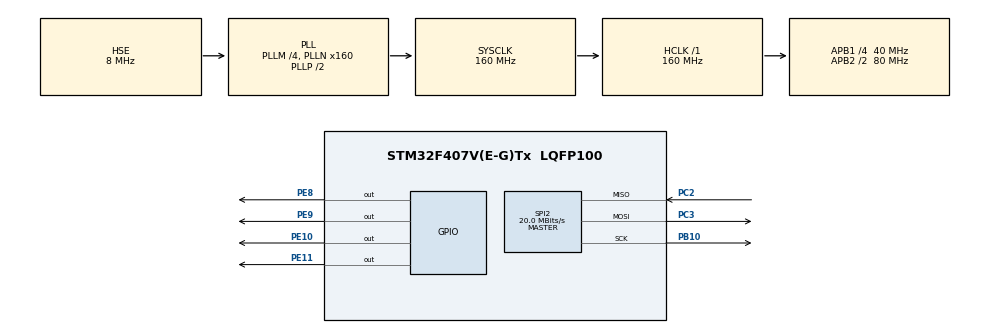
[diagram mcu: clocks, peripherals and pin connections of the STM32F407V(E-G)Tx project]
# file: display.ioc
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ADC1.Channel-0\#ChannelRegularConversion=ADC_CHANNEL_TEMPSENSOR
ADC1.ClockPrescaler=ADC_CLOCK_SYNC_PCLK_DIV8
ADC1.NbrOfConversionFlag=1
ADC1.Rank-0\#ChannelRegularConversion=1
ADC1.SamplingTime-0\#ChannelRegularConversion=ADC_SAMPLETIME_3CYCLES
ADC1.master=1
Mcu.Family=STM32F4
Mcu.Name=STM32F407V(E-G)Tx
Mcu.Package=LQFP100
NVIC.PriorityGroup=NVIC_PRIORITYGROUP_4
PA13.Mode=Trace_Asynchronous_SW
PA13.Signal=SYS_JTMS-SWDIO
PA14.Mode=Trace_Asynchronous_SW
PA14.Signal=SYS_JTCK-SWCLK
PB10.Mode=Full_Duplex_Master
PB10.Signal=SPI2_SCK
PB3.Mode=Trace_Asynchronous_SW
PB3.Signal=SYS_JTDO-SWO
PC14-OSC32_IN.Mode=LSE-External-Oscillator
PC14-OSC32_IN.Signal=RCC_OSC32_IN
PC15-OSC32_OUT.Mode=LSE-External-Oscillator
PC15-OSC32_OUT.Signal=RCC_OSC32_OUT
PC2.Mode=Full_Duplex_Master
PC2.Signal=SPI2_MISO
PC3.Mode=Full_Duplex_Master
PC3.Signal=SPI2_MOSI
PE10.GPIO_ModeDefaultOutputPP=GPIO_MODE_OUTPUT_PP
PE10.GPIO_PuPd=GPIO_NOPULL
PE10.GPIO_Speed=GPIO_SPEED_FREQ_HIGH
PE10.Signal=GPIO_Output
PE11.GPIO_ModeDefaultOutputPP=GPIO_MODE_OUTPUT_PP
PE11.GPIO_PuPd=GPIO_NOPULL
PE11.GPIO_Speed=GPIO_SPEED_FREQ_HIGH
PE11.Signal=GPIO_Output
PE8.GPIO_ModeDefaultOutputPP=GPIO_MODE_OUTPUT_PP
PE8.GPIO_PuPd=GPIO_NOPULL
PE8.GPIO_Speed=GPIO_SPEED_FREQ_HIGH
PE8.Signal=GPIO_Output
PE9.GPIO_ModeDefaultOutputPP=GPIO_MODE_OUTPUT_PP
PE9.GPIO_PuPd=GPIO_NOPULL
PE9.GPIO_Speed=GPIO_SPEED_FREQ_HIGH
PE9.Signal=GPIO_Output
PH0-OSC_IN.Mode=HSE-External-Oscillator
PH0-OSC_IN.Signal=RCC_OSC_IN
PH1-OSC_OUT.Mode=HSE-External-Oscillator
PH1-OSC_OUT.Signal=RCC_OSC_OUT
ProjectManager.HeapSize=0x200
ProjectManager.StackSize=0x400
ProjectManager.TargetToolchain=MDK-ARM V5.32
RCC.48MHZClocksFreq_Value=80000000
RCC.AHBFreq_Value=160000000
RCC.APB1CLKDivider=RCC_HCLK_DIV4
RCC.APB1Freq_Value=40000000
RCC.APB1TimFreq_Value=80000000
RCC.APB2CLKDivider=RCC_HCLK_DIV2
RCC.APB2Freq_Value=80000000
RCC.APB2TimFreq_Value=160000000
RCC.CortexFreq_Value=160000000
RCC.HCLKFreq_Value=160000000
RCC.HSE_VALUE=8000000
RCC.HSI_VALUE=16000000
RCC.PLLM=4
RCC.PLLN=160
RCC.PLLSourceVirtual=RCC_PLLSOURCE_HSE
RCC.RCC_RTC_Clock_Source=RCC_RTCCLKSOURCE_LSE
RCC.SYSCLKFreq_VALUE=160000000
RCC.SYSCLKSource=RCC_SYSCLKSOURCE_PLLCLK
RCC.VCOOutputFreq_Value=320000000
SPI2.BaudRatePrescaler=SPI_BAUDRATEPRESCALER_2
SPI2.CalculateBaudRate=20.0 MBits/s
SPI2.Direction=SPI_DIRECTION_2LINES
SPI2.Mode=SPI_MODE_MASTER
SPI2.VirtualType=VM_MASTER
VP_ADC1_TempSens_Input.Mode=IN-TempSens
VP_RTC_VS_RTC_Activate.Mode=RTC_Enabled
board=custom

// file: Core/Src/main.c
/* USER CODE BEGIN Header */
/**
  ******************************************************************************
  * @file           : main.c
  * @brief          : Main program body
  ******************************************************************************
  * @attention
  *
  * <h2><center>&copy; Copyright (c) 2022 STMicroelectronics.
  * All rights reserved.</center></h2>
  *
  * This software component is licensed by ST under BSD 3-Clause license,
  * the "License"; You may not use this file except in compliance with the
  * License. You may obtain a copy of the License at:
  *                        opensource.org/licenses/BSD-3-Clause
  *
  ******************************************************************************
  */
/* USER CODE END Header */
#include "main.h"
#include "st7735.h"
#include "string.h"
#include <stdio.h>
#include "math.h"
/* USER CODE BEGIN Includes */
uint8_t r = 1;
SPI_HandleTypeDef hspi2;
/* USER CODE END Includes */

ADC_HandleTypeDef hadc1;

RTC_HandleTypeDef hrtc;

SPI_HandleTypeDef hspi2;

RTC_TimeTypeDef sTime = {0};
RTC_DateTypeDef sDate = {0};

void SystemClock_Config(void);
static void MX_GPIO_Init(void);
static void MX_SPI2_Init(void);
static void MX_ADC1_Init(void);
static void MX_RTC_Init(void);

void demoTFT(void)
{
ST7735_SetRotation(r);

 ST7735_FillScreen(ST7735_BLACK);

 for(int x = 0; x < ST7735_GetWidth(); x++)
 {
   ST7735_DrawPixel(x, 0, ST7735_WHITE);
   ST7735_DrawPixel(x, ST7735_GetHeight() - 1, ST7735_WHITE);
 }

 for(int y = 0; y < ST7735_GetHeight(); y++)
 {
   ST7735_DrawPixel(0, y, ST7735_WHITE);
   ST7735_DrawPixel(ST7735_GetWidth() - 1, y, ST7735_WHITE);
 }

 ST7735_DrawLine(0, 0, ST7735_GetWidth(), ST7735_GetHeight(), ST7735_WHITE);
 ST7735_DrawLine(ST7735_GetWidth(), 0, 0, ST7735_GetHeight(), ST7735_WHITE);

 HAL_Delay(2000);

 ST7735_FillScreen(ST7735_BLACK);

 for (int i = 0; i < ST7735_GetHeight(); i += 4)
 {
  ST7735_DrawFastHLine(0, i, ST7735_GetWidth() - 1, ST7735_WHITE);
 }

 for (int i = 0; i < ST7735_GetWidth(); i += 4)
 {
  ST7735_DrawFastVLine(i, 0, ST7735_GetHeight() - 1, ST7735_WHITE);
 }

 HAL_Delay(2000);

 // Check fonts
 ST7735_FillScreen(ST7735_BLACK);
 ST7735_DrawString(0, 0, "Font_7x10, red on black, lorem ipsum dolor sit amet", Font_7x10, ST7735_RED, ST7735_BLACK);
 ST7735_DrawString(0, 3*10, "Font_11x18, green, lorem ipsum", Font_11x18, ST7735_GREEN, ST7735_BLACK);
 ST7735_DrawString(0, 3*10+3*18, "Font_16x26", Font_16x26, ST7735_BLUE, ST7735_BLACK);
 HAL_Delay(2000);

 // Check colors
 ST7735_FillScreen(ST7735_BLACK);
 ST7735_DrawString(0, 0, "BLACK", Font_11x18, ST7735_WHITE, ST7735_BLACK);
 HAL_Delay(500);

 ST7735_FillScreen(ST7735_BLUE);
 ST7735_DrawString(0, 0, "BLUE", Font_11x18, ST7735_BLACK, ST7735_BLUE);
 HAL_Delay(500);

 ST7735_FillScreen(ST7735_RED);
 ST7735_DrawString(0, 0, "RED", Font_11x18, ST7735_BLACK, ST7735_RED);
 HAL_Delay(500);

 ST7735_FillScreen(ST7735_GREEN);
 ST7735_DrawString(0, 0, "GREEN", Font_11x18, ST7735_BLACK, ST7735_GREEN);
 HAL_Delay(500);

 ST7735_FillScreen(ST7735_CYAN);
 ST7735_DrawString(0, 0, "CYAN", Font_11x18, ST7735_BLACK, ST7735_CYAN);
 HAL_Delay(500);

 ST7735_FillScreen(ST7735_MAGENTA);
 ST7735_DrawString(0, 0, "MAGENTA", Font_11x18, ST7735_BLACK, ST7735_MAGENTA);
 HAL_Delay(500);

 ST7735_FillScreen(ST7735_YELLOW);
 ST7735_DrawString(0, 0, "YELLOW", Font_11x18, ST7735_BLACK, ST7735_YELLOW);
 HAL_Delay(500);

 ST7735_FillScreen(ST7735_WHITE);
 ST7735_DrawString(0, 0, "WHITE", Font_11x18, ST7735_BLACK, ST7735_WHITE);
 HAL_Delay(500);

 // Draw circles
 ST7735_FillScreen(ST7735_BLACK);
 for (int i = 0; i < ST7735_GetHeight() / 2; i += 2)
 {
  ST7735_DrawCircle(ST7735_GetWidth() / 2, ST7735_GetHeight() / 2, i, ST7735_YELLOW);
 }
 HAL_Delay(1000);

 ST7735_FillScreen(ST7735_BLACK);
 ST7735_FillTriangle(0, 0, ST7735_GetWidth() / 2, ST7735_GetHeight(), ST7735_GetWidth(), 0, ST7735_RED);
 HAL_Delay(1000);

}

double mapTimeToDeg( uint8_t hour, uint8_t minute){
	uint8_t hr = hour < 13 ? hour : hour - 12;
	return ((30 * hr) + (0.5 * minute)) * 0.0174533;
}
int main(void)
{

  /* MCU Configuration--------------------------------------------------------*/

  /* Reset of all peripherals, Initializes the Flash interface and the Systick. */
  HAL_Init();

  /* Configure the system clock */
  SystemClock_Config();

  /* Initialize all configured peripherals */
  MX_GPIO_Init();
  MX_SPI2_Init();
  MX_ADC1_Init();
  MX_RTC_Init();
	ST7735_Init();
	ST7735_SetRotation(1);
	ST7735_FillScreen(ST7735_WHITE);

	char day[4];
  char time[8];
	char date[10];
	double degree;

  while (1)
  {

		HAL_RTC_GetTime(&hrtc, &sTime, RTC_FORMAT_BIN); // RTC_FORMAT_BIN , RTC_FORMAT_BCD
		HAL_RTC_GetDate(&hrtc, &sDate, FORMAT_BIN);
		sprintf(time,"%.2d:%.2d:%.2d",sTime.Hours,sTime.Minutes,sTime.Seconds);
		sprintf(date,"%.2d/%.2d/20%.2d",sDate.Date,sDate.Month,sDate.Year);
		ST7735_DrawLine(25,25,((sin(degree)*23)+25),((-cos(degree)*25)+25),ST7735_WHITE);
    degree = mapTimeToDeg(sTime.Hours,sTime.Minutes);
    ST7735_DrawLine(25,25,((sin(degree)*23)+25),((-cos(degree)*25)+25),ST7735_BLACK);
		ST7735_DrawCircle(25,25,23,ST7735_BLACK);

		switch (sDate.WeekDay)
		{
			case 1 : strcpy(day, "MON\0");  break;
			case 2 : strcpy(day, "TUE\0");  break;
			case 3 : strcpy(day, "WED\0");  break;
			case 4 : strcpy(day, "THU\0");  break;
			case 5 : strcpy(day, "FRI\0");  break;
			case 6 : strcpy(day, "SAT\0");  break;
			case 7 : strcpy(day, "SUN\0");  break;
			default : break;

		};

    ST7735_DrawString(15, 55, time, Font_16x26, ST7735_BLACK, ST7735_WHITE);
    ST7735_DrawString(25, 90, date, Font_11x18, ST7735_BLACK, ST7735_WHITE);
		ST7735_DrawString(85, 20, day, Font_11x18, ST7735_BLACK, ST7735_WHITE);

		if(!HAL_GPIO_ReadPin(GPIOE, GPIO_PIN_3)){
			if(sTime.Minutes == 59){
				sTime.Minutes = 0;
			} else sTime.Minutes +=1;
      sTime.Seconds = 0;
			HAL_RTC_SetTime(&hrtc, &sTime, RTC_FORMAT_BIN);
			HAL_Delay(150);
		}
		if(!HAL_GPIO_ReadPin(GPIOE, GPIO_PIN_4)){
      if(sTime.Hours==23){
				sTime.Hours = 0;
			} else sTime.Hours +=1;
      sTime.Seconds = 0;
			HAL_RTC_SetTime(&hrtc, &sTime, RTC_FORMAT_BIN);
			HAL_Delay(150);
		}
  }
}

void SystemClock_Config(void)
{
  RCC_OscInitTypeDef RCC_OscInitStruct = {0};
  RCC_ClkInitTypeDef RCC_ClkInitStruct = {0};

  /** Configure the main internal regulator output voltage
  */
  __HAL_RCC_PWR_CLK_ENABLE();
  __HAL_PWR_VOLTAGESCALING_CONFIG(PWR_REGULATOR_VOLTAGE_SCALE1);
  /** Initializes the RCC Oscillators according to the specified parameters
  * in the RCC_OscInitTypeDef structure.
  */
  RCC_OscInitStruct.OscillatorType = RCC_OSCILLATORTYPE_HSE|RCC_OSCILLATORTYPE_LSE;
  RCC_OscInitStruct.HSEState = RCC_HSE_ON;
  RCC_OscInitStruct.LSEState = RCC_LSE_ON;
  RCC_OscInitStruct.PLL.PLLState = RCC_PLL_ON;
  RCC_OscInitStruct.PLL.PLLSource = RCC_PLLSOURCE_HSE;
  RCC_OscInitStruct.PLL.PLLM = 4;
  RCC_OscInitStruct.PLL.PLLN = 160;
  RCC_OscInitStruct.PLL.PLLP = RCC_PLLP_DIV2;
  RCC_OscInitStruct.PLL.PLLQ = 4;
  if (HAL_RCC_OscConfig(&RCC_OscInitStruct) != HAL_OK)
  {
    Error_Handler();
  }
  /** Initializes the CPU, AHB and APB buses clocks
  */
  RCC_ClkInitStruct.ClockType = RCC_CLOCKTYPE_HCLK|RCC_CLOCKTYPE_SYSCLK
                              |RCC_CLOCKTYPE_PCLK1|RCC_CLOCKTYPE_PCLK2;
  RCC_ClkInitStruct.SYSCLKSource = RCC_SYSCLKSOURCE_PLLCLK;
  RCC_ClkInitStruct.AHBCLKDivider = RCC_SYSCLK_DIV1;
  RCC_ClkInitStruct.APB1CLKDivider = RCC_HCLK_DIV4;
  RCC_ClkInitStruct.APB2CLKDivider = RCC_HCLK_DIV2;

  if (HAL_RCC_ClockConfig(&RCC_ClkInitStruct, FLASH_LATENCY_5) != HAL_OK)
  {
    Error_Handler();
  }
}

static void MX_ADC1_Init(void)
{

  ADC_ChannelConfTypeDef sConfig = {0};

  /** Configure the global features of the ADC (Clock, Resolution, Data Alignment and number of conversion)
  */
  hadc1.Instance = ADC1;
  hadc1.Init.ClockPrescaler = ADC_CLOCK_SYNC_PCLK_DIV8;
  hadc1.Init.Resolution = ADC_RESOLUTION_12B;
  hadc1.Init.ScanConvMode = DISABLE;
  hadc1.Init.ContinuousConvMode = DISABLE;
  hadc1.Init.DiscontinuousConvMode = DISABLE;
  hadc1.Init.ExternalTrigConvEdge = ADC_EXTERNALTRIGCONVEDGE_NONE;
  hadc1.Init.ExternalTrigConv = ADC_SOFTWARE_START;
  hadc1.Init.DataAlign = ADC_DATAALIGN_RIGHT;
  hadc1.Init.NbrOfConversion = 1;
  hadc1.Init.DMAContinuousRequests = DISABLE;
  hadc1.Init.EOCSelection = ADC_EOC_SINGLE_CONV;
  if (HAL_ADC_Init(&hadc1) != HAL_OK)
  {
    Error_Handler();
  }
  /** Configure for the selected ADC regular channel its corresponding rank in the sequencer and its sample time.
  */
  sConfig.Channel = ADC_CHANNEL_TEMPSENSOR;
  sConfig.Rank = 1;
  sConfig.SamplingTime = ADC_SAMPLETIME_3CYCLES;
  if (HAL_ADC_ConfigChannel(&hadc1, &sConfig) != HAL_OK)
  {
    Error_Handler();
  }

}

static void MX_RTC_Init(void)
{

  /** Initialize RTC Only
  */
  hrtc.Instance = RTC;
  hrtc.Init.HourFormat = RTC_HOURFORMAT_24;
  hrtc.Init.AsynchPrediv = 127;
  hrtc.Init.SynchPrediv = 255;
  hrtc.Init.OutPut = RTC_OUTPUT_DISABLE;
  hrtc.Init.OutPutPolarity = RTC_OUTPUT_POLARITY_HIGH;
  hrtc.Init.OutPutType = RTC_OUTPUT_TYPE_OPENDRAIN;
  if (HAL_RTC_Init(&hrtc) != HAL_OK)
  {
    Error_Handler();
  }

}

static void MX_SPI2_Init(void)
{

  /* SPI2 parameter configuration*/
  hspi2.Instance = SPI2;
  hspi2.Init.Mode = SPI_MODE_MASTER;
  hspi2.Init.Direction = SPI_DIRECTION_2LINES;
  hspi2.Init.DataSize = SPI_DATASIZE_8BIT;
  hspi2.Init.CLKPolarity = SPI_POLARITY_LOW;
  hspi2.Init.CLKPhase = SPI_PHASE_1EDGE;
  hspi2.Init.NSS = SPI_NSS_SOFT;
  hspi2.Init.BaudRatePrescaler = SPI_BAUDRATEPRESCALER_2;
  hspi2.Init.FirstBit = SPI_FIRSTBIT_MSB;
  hspi2.Init.TIMode = SPI_TIMODE_DISABLE;
  hspi2.Init.CRCCalculation = SPI_CRCCALCULATION_DISABLE;
  hspi2.Init.CRCPolynomial = 10;
  if (HAL_SPI_Init(&hspi2) != HAL_OK)
  {
    Error_Handler();
  }

}

static void MX_GPIO_Init(void)
{
  GPIO_InitTypeDef GPIO_InitStruct = {0};

  /* GPIO Ports Clock Enable */
  __HAL_RCC_GPIOC_CLK_ENABLE();
  __HAL_RCC_GPIOH_CLK_ENABLE();
  __HAL_RCC_GPIOE_CLK_ENABLE();
  __HAL_RCC_GPIOB_CLK_ENABLE();
  __HAL_RCC_GPIOA_CLK_ENABLE();

  /*Configure GPIO pin Output Level */
  HAL_GPIO_WritePin(GPIOE, GPIO_PIN_8|GPIO_PIN_9|GPIO_PIN_10|GPIO_PIN_11, GPIO_PIN_RESET);

  /*Configure GPIO pins : PE8 PE9 PE10 PE11 */
  GPIO_InitStruct.Pin = GPIO_PIN_8|GPIO_PIN_9|GPIO_PIN_10|GPIO_PIN_11;
  GPIO_InitStruct.Mode = GPIO_MODE_OUTPUT_PP;
  GPIO_InitStruct.Pull = GPIO_NOPULL;
  GPIO_InitStruct.Speed = GPIO_SPEED_FREQ_HIGH;
  HAL_GPIO_Init(GPIOE, &GPIO_InitStruct);

	GPIO_InitStruct.Pin = GPIO_PIN_3|GPIO_PIN_4;
  GPIO_InitStruct.Mode = GPIO_MODE_INPUT;
  GPIO_InitStruct.Pull = GPIO_PULLUP;
  HAL_GPIO_Init(GPIOE, &GPIO_InitStruct);

}

void Error_Handler(void)
{
  __disable_irq();
  while (1)
  {
  }
}

/************************ (C) COPYRIGHT STMicroelectronics *****END OF FILE****/
